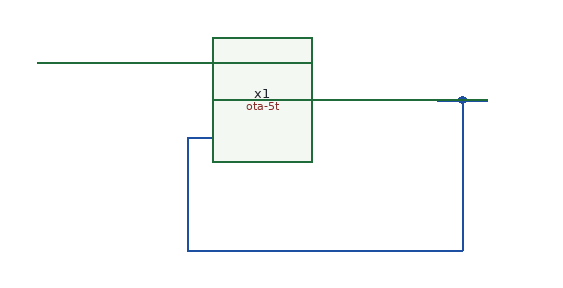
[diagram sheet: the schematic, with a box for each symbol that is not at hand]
v {xschem version=3.4.8RC file_version=1.3}
G {}
K {}
V {}
S {}
F {}
E {}
N -100 30 -80 30 {lab=#net1}
N -100 30 -100 120 {lab=#net1}
N -100 120 120 120 {lab=#net1}
N 120 0 120 120 {lab=#net1}
N 100 -0 120 0 {lab=#net1}
N 120 -0 140 0 {lab=#net1}
N -220 -30 -80 -30 {lab=#net2}
C {/foss/designs/004_Real_Circuits/ota-5t.sym} 0 0 0 0 {name=x1}
